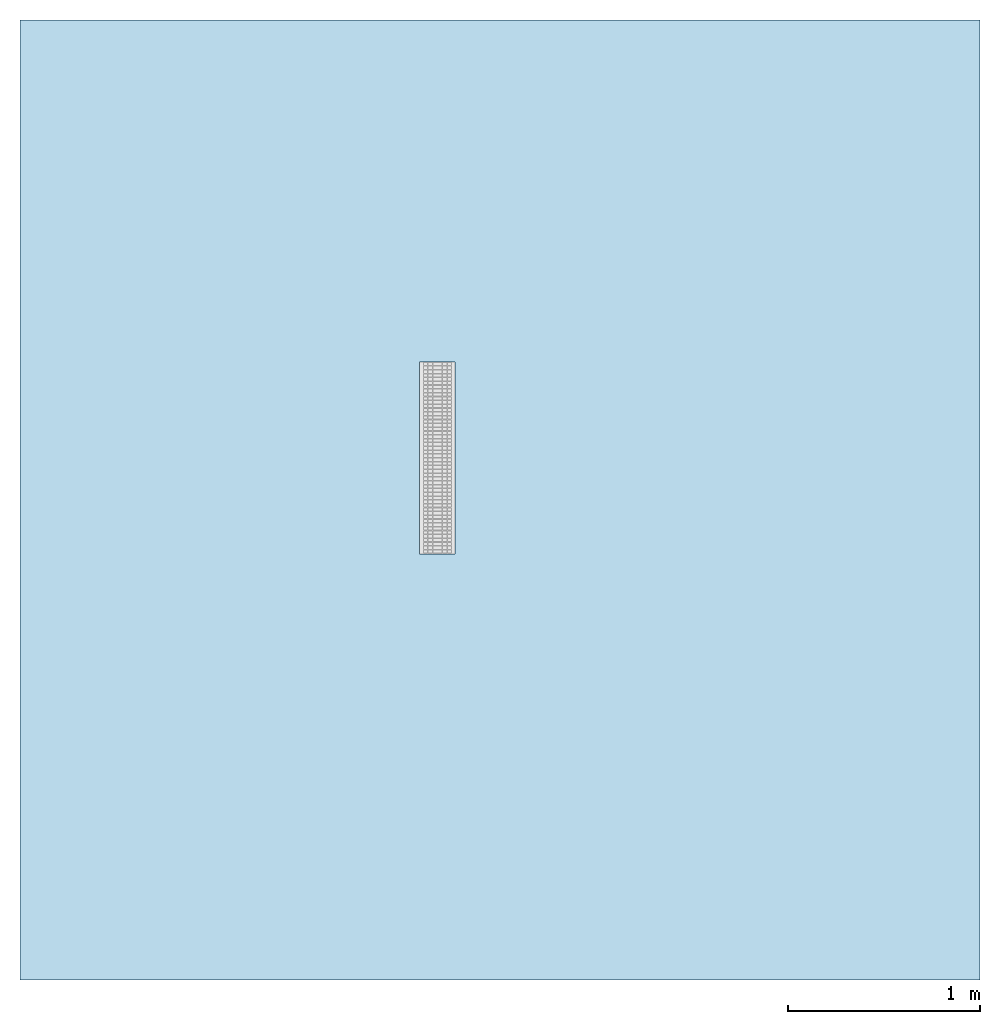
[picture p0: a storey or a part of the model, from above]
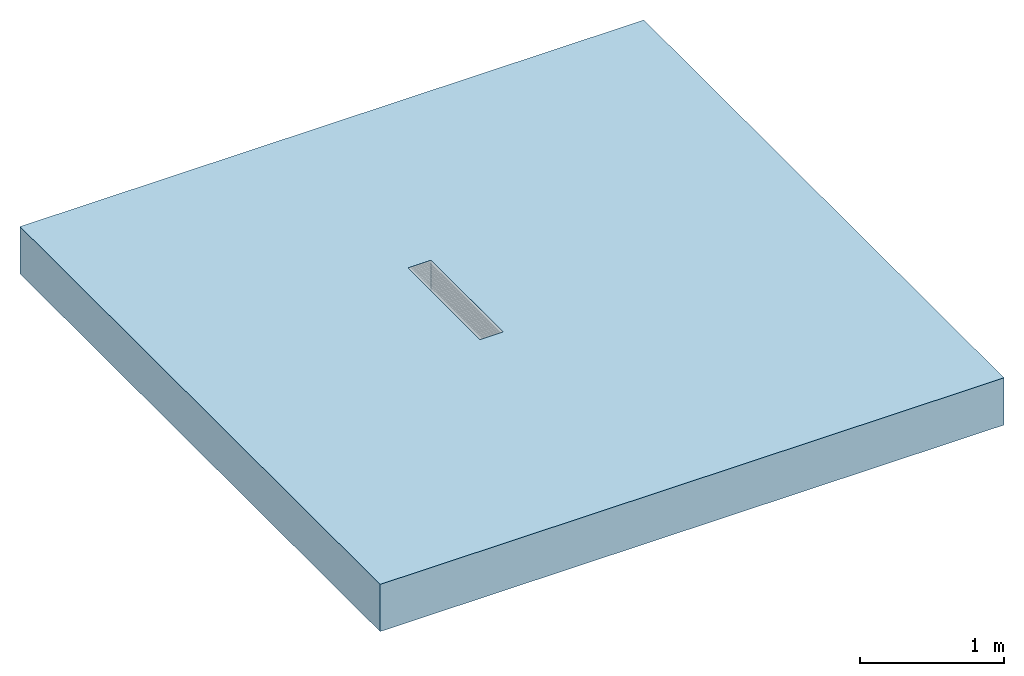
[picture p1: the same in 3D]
Properties of the parts of a building model (IFC2X3)

# File
Description: ViewDefinition [CoordinationView]
File name: 24151 - No 10.0 Constant Depth Channel - 1000mm LG - Invert Depth 235mm.ifc
Time: 2013-10-17T16:56:21
Written by: Autodesk Revit 2013
Made in: 20120221_2030(x64)

# IfcProject, Project Number
LongName: Project Name; Phase: Project Status

# IfcSite, Default
RefLatitude: 42, 21, 30, 344238; RefLongitude: -71, -3, -35, -194702; RefElevation: 0 mm

# IfcBuilding
Pset_BuildingCommon - NumberOfStoreys: 1
Other - Project Address: ## Street City, State Zip; Project Status: Project Status; Project Number: Project Number; Project Name: Project Name; Project Issue Date: Issue Date; Client Name: Owner

# IfcBuildingStorey, Level 1
LongName: Level 1; Elevation: 0 mm
Constraints - Elevation Base: 0; Elevation: 0 mm
Graphics - Symbol at End 2 Default: yes; Color: 0; Symbol at End 1 Default: no; Symbol: M_Level Head - Circle: M_Level Head - Circle; Line Pattern: Center; Line Weight: 1
Identity Data - Building Story: yes; Name: Level 1; Structural: no
Dimensions - Computation Height: 0 mm

# IfcBuildingElementProxy: 24151 - No 10.0 Constant Depth Channel - 1000mm LG - Invert Depth 235mm, Civil-Drainage-Channel-ACO-MultiDrain-M150DS-Channel-System-Custom_Final FL:24151 - No 10.0 Constant Depth Channel - 1000mm LG - Invert Depth 235mm:24151 - No 10.0 Constant Depth Channel - 1000mm LG - Invert Depth 235mm:199235
In: Level 1
Material: Vienite® Synthetic Resin Concrete
Construction - 23159 - Universal Endcap (Male End): no; 13048 - Grating - Mesh - Stainless Steel - 1000mm Long: no; 23159 - Universal Endcap (Female End): no; 13049 - Grating - Mesh - Stainless Steel - 500mm Long: no; 24157_Shallow Depth Channel with seal: no; Grating_1000mm: yes; Constant Depth Channel_1000: yes; 24156_Shallow Depth Channel: no; 24158_Sump Unit: no; Constant Depth Channel_500: no; Grating_500mm: no
Dimensions - EndCap Position: 1000 mm; Custom cut void length: 0 mm; FloorCut_Length: -1000 mm; Length: 1000 mm; Volume: 15825930 mm3; EndCap_Height: 260 mm; FloorCut_Depth: 260 mm; InvDepth: 160 mm; Depth: 260 mm; FloorCut_Width: 185 mm; FloorCut_HorPosition: 92.5 mm; Mesh grating length: -1000 mm
Phasing - Phase Created: New Construction
Constraints - Moves With Nearby Elements: no; Level: Level: Level 1
Pset_BuildingElementProxyCommon - Reference: 24151 - No 10.0 Constant Depth Channel - 1000mm LG - Invert Depth 235mm
Materials and Finishes - Channel Colour: Brown; Edge Rail Material: Stainless Steel Grade 304; Edge Rail Colour: Self; Channel Material: Vienite® Synthetic Resin Concrete
General - TagNumber: 0; SerialNumber: 0
Model Properties - Grating Product code 13049: Load Class C250 - Mesh Stainless Steel Grade 304 13049DL 500mm long - 23x17mm hole - Intake Area 115100mm²/m- 3.7kg; Grating Product code 13048: Load Class C250 - Mesh Stainless Steel Grade 304 13048DL 1000mm long - 23x17mm hole - Intake Area 115100mm²/m- 7.4kg; End Cap Product code 23159: No 306 Universal End Cap - 185mm wide x 310mm long - Spigot Ø160mm x 75mm long - Silver - Polypropylene - 0.3kg
Identity Data - Assembly Code: D2040; Model Description: Channel drainage system; Installation guidelines: http://www.aco.co.uk/download.php?id=173; Watermarked By: www.aco.co.uk; e-mail Technical: technical@aco.co.uk; Type Comments: ACO MultiDrain M150DS 10.0 Constant Depth Channel 1000mm Long; Fax: +44 (0)1462 815895; Product Code: 24151; Watermark 2: This file is water marked and users are prohibited to reproduce, adapt, distribute this information; Cost: 0; Price: POA - contact ACO; Watermark 1: This file is the property of ACO Technologies PLC; Manufacturer: ACO Technologies plc - ACO Water Management Division; OmniClass Number: 23.70.50.24; Product brochure: http://www.aco.co.uk/download.php?id=173; Maintenance guidelines: http://www.aco.co.uk/download.php?id=173; Watermarked With: BIM Manager Premium Suite; Assembly Description: Rain Water Drainage; Model: ACO MultiDrain MD - M150DS; Telephone: +44 (0)1462 816666; URL: www.aco.co.uk; Address: ACO Business Park, Hitchin Road, Shefford, Bedfordshire, United Kingdom SG17 5TE; e-mail Sales: customersupport@aco.co.uk; Product Page URL: http://www.aco.co.uk/product_detail.php?id=15; OmniClass Title: Rainwater Removal
Data - Hydraulic Performance: http://www.aco.co.uk/download.php?id=173; Product Standard: BS EN 1433:2002, CE marked; Invert Depth: 235mm; Load Class: A 15 - D 400; Concrete Surround Volume - Load Class B 125 - C 250 - Concrete Pavement: 0.16m³/m; Concrete Surround Volume - Load Class D 400 - Concrete Pavement: 0.23m³/m; Product Dimensions: 1000mm x 185mm x 260mm (LxWxH); Product Weight: 26.7 Kg; Concrete Surround Volume - Load Class A 15 - Concrete Pavement: 0.10m³/m; ACO Hydraulic Design Software: http://www.acodesign.co.uk; Installation - Concrete Grade: Refer to brochure; Pre-formed Outlet Ø: N/A; Channel C.S.A: 0.026m²
Other - CreatedBy: www.aco.co.uk; Revision: 1
Green Building Properties - Edge Rail Recyclable: Fully recyclable; Channel Recyclable: Fully recyclable; Edge Rail Recycled Material Content: Between 40% - 90%; Channel Recycled Material Content: 20% minimum

# IfcOpeningElement: Recess
In: Level 1
Phasing - Phase Created: New Construction
Dimensions - Area: 25000000 mm2; Volume: 9951900000 mm3; Thickness: 400 mm; Perimeter: 20000 mm
Structural - Enable Analytical Model: no; Structural: no
Constraints - Height Offset From Level: 0 mm; Related to Mass: no; Room Bounding: yes; Level: Level: Level 1
Analytical Properties - Roughness: 1; Absorptance: 0.1
Graphics - Coarse Scale Fill Color: 0
Construction - Default Thickness: 400 mm; Function: 0

# IfcSlab: Floor:Generic Floor - 400mm, Floor:Generic Floor - 400mm:193825
In: Level 1
PredefinedType: FLOOR; Material: Default Roof 400 mm
Phasing - Phase Created: New Construction
Dimensions - Area: 25000000 mm2; Volume: 9951900000 mm3; Thickness: 400 mm; Perimeter: 20000 mm
Structural - Enable Analytical Model: no; Structural: no
Constraints - Height Offset From Level: 0 mm; Related to Mass: no; Room Bounding: yes; Level: Level: Level 1
Pset_SlabCommon - Reference: Generic Floor - 400mm; IsExternal: no; LoadBearing: yes
Analytical Properties - Roughness: 1; Absorptance: 0.1
Graphics - Coarse Scale Fill Color: 0
Construction - Default Thickness: 400 mm; Function: 0
